One B-rep face of a CAD part: STEP entity #646.
In plain terms, the cylindrical face has radius 32.5 mm (diameter 65 mm), a partial arc.
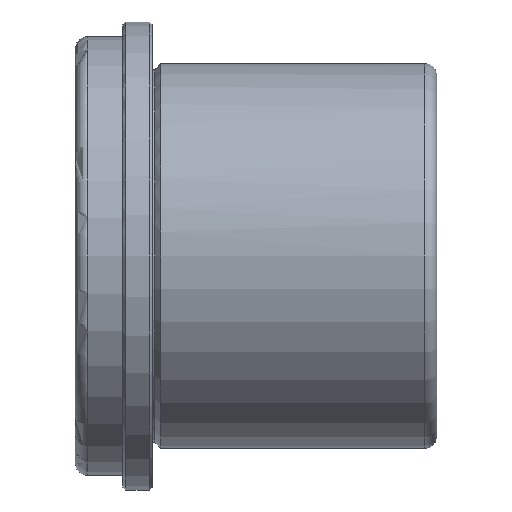
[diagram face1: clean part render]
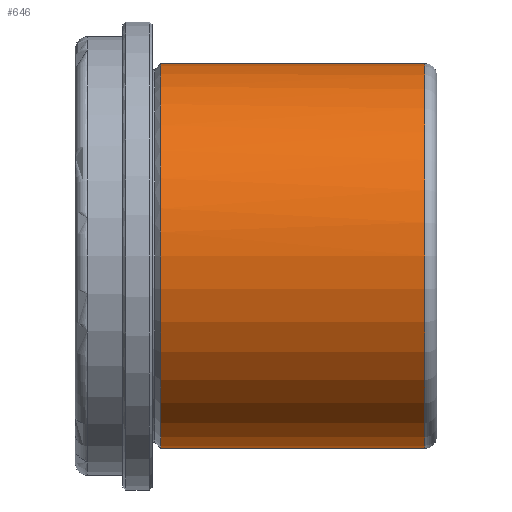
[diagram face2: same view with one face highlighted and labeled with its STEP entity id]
Its self-contained STEP definition (entity closure, numbers rounded to 3 decimals):
#419=CARTESIAN_POINT('Line Origine',(48.,0.,32.5)) ;
#423=CARTESIAN_POINT('Vertex',(46.,0.,32.5)) ;
#425=CARTESIAN_POINT('Vertex',(1.414,0.,32.5)) ;
#439=CARTESIAN_POINT('Vertex',(46.,0.,-32.5)) ;
#442=CARTESIAN_POINT('Line Origine',(48.,0.,-32.5)) ;
#446=CARTESIAN_POINT('Vertex',(1.414,0.,-32.5)) ;
#603=CARTESIAN_POINT('Axis2P3D Location',(48.,0.,0.)) ;
#608=CARTESIAN_POINT('Axis2P3D Location',(46.,0.,0.)) ;
#612=CARTESIAN_POINT('Vertex',(46.,-32.5,0.)) ;
#615=CARTESIAN_POINT('Axis2P3D Location',(46.,0.,0.)) ;
#621=CARTESIAN_POINT('Control Point',(1.414,0.,32.5)) ;
#622=CARTESIAN_POINT('Control Point',(1.414,-5.105,32.5)) ;
#623=CARTESIAN_POINT('Control Point',(1.414,-10.21,31.498)) ;
#624=CARTESIAN_POINT('Control Point',(1.414,-15.052,29.492)) ;
#625=CARTESIAN_POINT('Control Point',(1.414,-23.69,23.69)) ;
#626=CARTESIAN_POINT('Control Point',(1.414,-29.492,15.052)) ;
#627=CARTESIAN_POINT('Control Point',(1.414,-31.498,10.21)) ;
#628=CARTESIAN_POINT('Control Point',(1.414,-32.5,5.105)) ;
#629=CARTESIAN_POINT('Control Point',(1.414,-32.5,0.)) ;
#630=CARTESIAN_POINT('Vertex',(1.414,-32.5,0.)) ;
#633=CARTESIAN_POINT('Axis2P3D Location',(1.414,0.,0.)) ;
#420=DIRECTION('Vector Direction',(-1.,0.,0.)) ;
#443=DIRECTION('Vector Direction',(-1.,0.,0.)) ;
#604=DIRECTION('Axis2P3D Direction',(-1.,-0.,-0.)) ;
#605=DIRECTION('Axis2P3D XDirection',(0.,0.,-1.)) ;
#609=DIRECTION('Axis2P3D Direction',(-1.,-0.,-0.)) ;
#616=DIRECTION('Axis2P3D Direction',(-1.,-0.,-0.)) ;
#634=DIRECTION('Axis2P3D Direction',(-1.,-0.,-0.)) ;
#606=AXIS2_PLACEMENT_3D('Cylinder Axis2P3D',#603,#604,#605) ;
#610=AXIS2_PLACEMENT_3D('Circle Axis2P3D',#608,#609,$) ;
#617=AXIS2_PLACEMENT_3D('Circle Axis2P3D',#615,#616,$) ;
#635=AXIS2_PLACEMENT_3D('Circle Axis2P3D',#633,#634,$) ;
#639=ORIENTED_EDGE('',*,*,#448,.T.) ;
#640=ORIENTED_EDGE('',*,*,#614,.F.) ;
#641=ORIENTED_EDGE('',*,*,#619,.F.) ;
#642=ORIENTED_EDGE('',*,*,#427,.T.) ;
#643=ORIENTED_EDGE('',*,*,#632,.T.) ;
#644=ORIENTED_EDGE('',*,*,#637,.T.) ;
#421=VECTOR('Line Direction',#420,1.) ;
#444=VECTOR('Line Direction',#443,1.) ;
#646=ADVANCED_FACE('CF 631 52 x 61',(#645),#607,.T.) ;
#620=B_SPLINE_CURVE_WITH_KNOTS('',5,(#621,#622,#623,#624,#625,#626,#627,#628,#629),.UNSPECIFIED.,.F.,.U.,(6,3,6),(-25.525,0.,25.525),.UNSPECIFIED.) ;
#611=CIRCLE('generated circle',#610,32.5) ;
#618=CIRCLE('generated circle',#617,32.5) ;
#636=CIRCLE('generated circle',#635,32.5) ;
#607=CYLINDRICAL_SURFACE('generated cylinder',#606,32.5) ;
#427=EDGE_CURVE('',#424,#426,#422,.T.) ;
#448=EDGE_CURVE('',#447,#440,#445,.F.) ;
#614=EDGE_CURVE('',#613,#440,#611,.F.) ;
#619=EDGE_CURVE('',#424,#613,#618,.F.) ;
#632=EDGE_CURVE('',#426,#631,#620,.T.) ;
#637=EDGE_CURVE('',#631,#447,#636,.F.) ;
#638=EDGE_LOOP('',(#639,#640,#641,#642,#643,#644)) ;
#645=FACE_OUTER_BOUND('',#638,.T.) ;
#422=LINE('Line',#419,#421) ;
#445=LINE('Line',#442,#444) ;
#424=VERTEX_POINT('',#423) ;
#426=VERTEX_POINT('',#425) ;
#440=VERTEX_POINT('',#439) ;
#447=VERTEX_POINT('',#446) ;
#613=VERTEX_POINT('',#612) ;
#631=VERTEX_POINT('',#630) ;
